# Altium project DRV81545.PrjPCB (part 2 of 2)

## Sheet DRV81545.SchDoc: DRV81545
size 431 x 279 mm; VersionControl_RevNumber: 1; Date: Not shown in title block; ApprovedBy: Not shown in title block; CheckedBy: Not shown in title block; Author: Not shown in title block; CompanyName: Not shown in title block; DrawnBy: Mojtaba Afshar; Engineer: Not shown in title block; Organization: Not shown in title block; Address1: Not shown in title block; Address2: Not shown in title block; Address3: Not shown in title block; Address4: Not shown in title block; DocumentNumber: 1; Revision: 1; SheetNumber: 3; SheetTotal: 5; PageSetup: Record=PageOptions¦CenterHorizontal=True¦CenterVertical=True¦PrintScale=1.00¦XCorrection=1.00¦YCorrection=1.00¦PrintKind=0¦BorderSize=5000000¦LeftOffset=0¦BottomOffset=0¦Orientation=2¦PaperLength=1000¦PaperWidth=1000¦Scale=100¦PaperSource=15¦PrintQuality=600¦MediaType=1¦DitherType=10¦PaperKind=Letter¦PrintScaleMode=1; VersionControl_ProjFolderRevNumber: 1; VersionControl_RevNumberShort: 1; VersionControl_ProjFolderRevNumberShort: 1; Orderable: DRV81545EVM

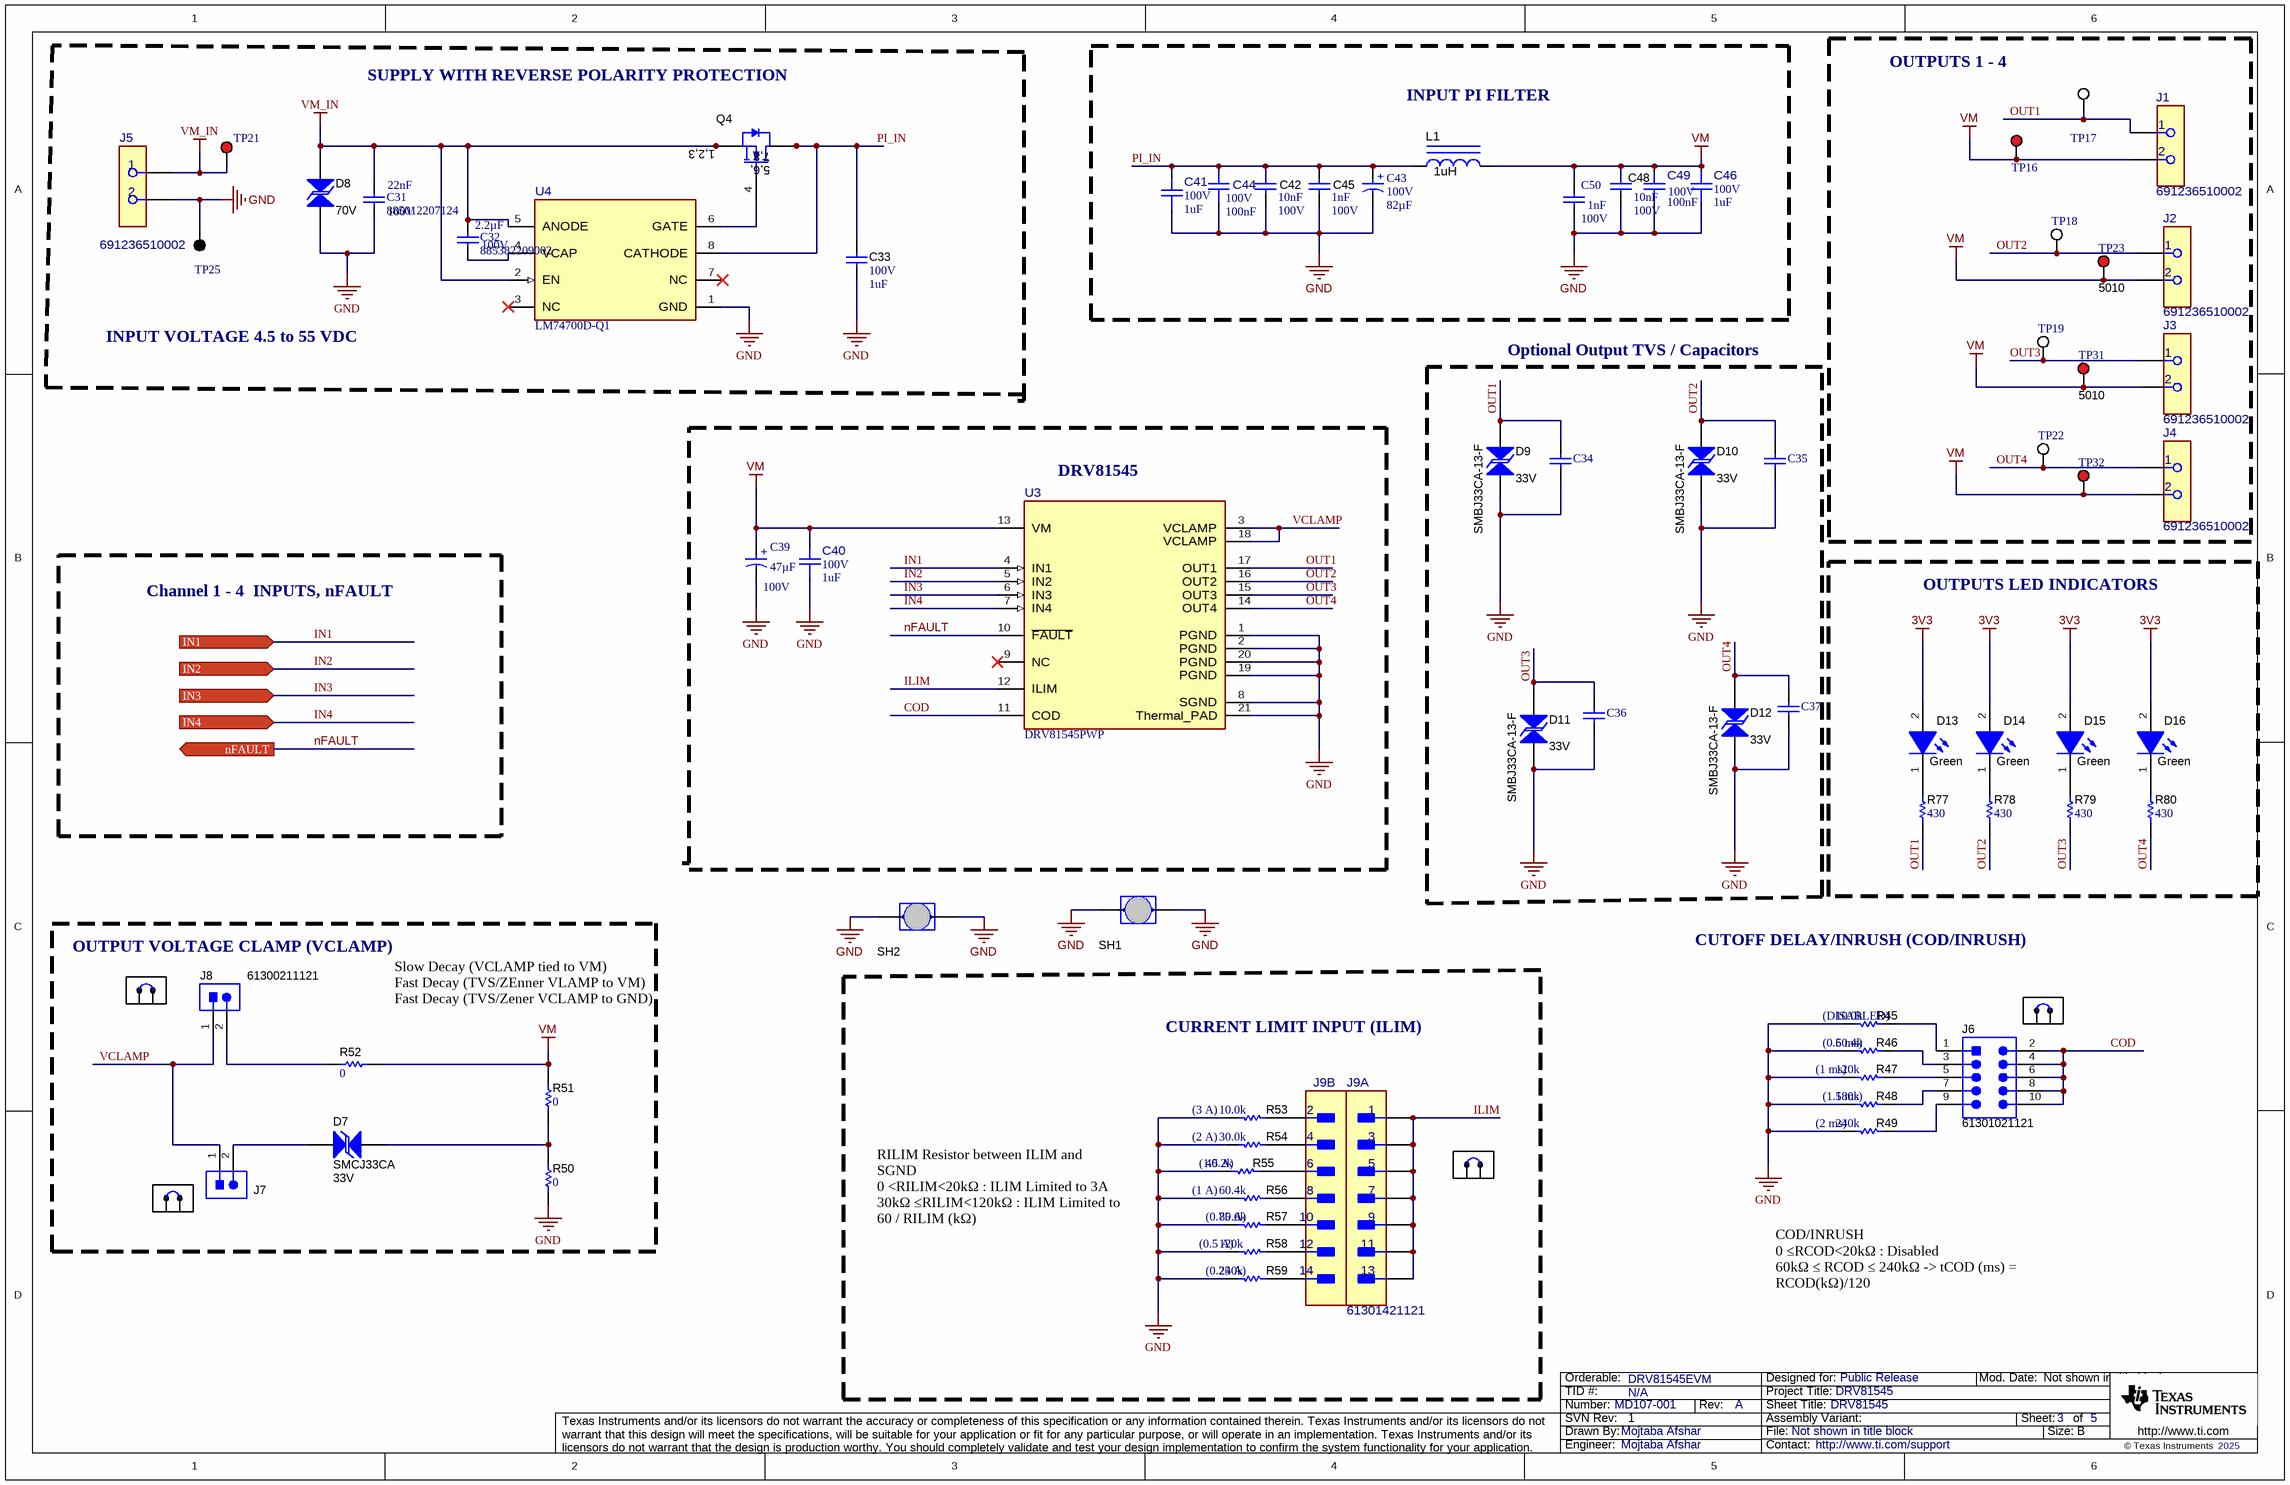
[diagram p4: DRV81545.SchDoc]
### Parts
C31  885012207124  Cap_F: 22nF  Rated Voltage (DC): 100V  [WCAP-CSGP_0805_L2W1.25H0.8_Reflow]
C32  885382209002  Cap_F: 2.2µF  Rated Voltage (DC): 100V  [WCAP-CSST_1210_L3.2W2.5H2.5]
C33  VDC_V: 100V  ValueDisplayed: 1uF  [0805_HV]  (hidden comment: C2012X7S2A105K125AB)
C34  885012207124  [WCAP-CSGP_0805_L2W1.25H0.8_Reflow]  (value not drawn)
C35  885012207124  [WCAP-CSGP_0805_L2W1.25H0.8_Reflow]  (value not drawn)
C36  885012207124  [WCAP-CSGP_0805_L2W1.25H0.8_Reflow]  (value not drawn)
C37  885012207124  [WCAP-CSGP_0805_L2W1.25H0.8_Reflow]  (value not drawn)
C39  Cap_F: 47µF  Rated Voltage (DC): 100V  [WCAP-ATUL_D10H12.5]  (hidden comment: 860040875002)
C40  VDC_V: 100V  ValueDisplayed: 1uF  [FP-885012209069_1210-MFG]  (hidden comment: 885012209069)
C41  VDC_V: 100V  ValueDisplayed: 1uF  [FP-885012209069_1210-MFG]  (hidden comment: 885012209069)
C42  Cap_F: 10nF  VDC_V: 100V  [0603]  (hidden comment: 885012206114)
C43  Cap_F: 82µF  Rated Voltage (DC): 100V  [WCAP-ATUL_D10H20]  (hidden comment: 860040875004)
C44  VDC_V: 100V  Cap_F: 100nF  [FP-885012206120_0603-MFG]  (hidden comment: 885012206120)
C45  Cap_F: 1nF  VDC_V: 100V  [0603]  (hidden comment: 06031C102KAT2A)
C46  VDC_V: 100V  ValueDisplayed: 1uF  [FP-885012209069_1210-MFG]  (hidden comment: 885012209069)
C48  Cap_F: 10nF  VDC_V: 100V  [0603]  (hidden comment: 885012206114)
C49  VDC_V: 100V  Cap_F: 100nF  [FP-885012206120_0603-MFG]  (hidden comment: 885012206120)
C50  value 1nF  Rated Voltage (DC): 100V  [WCAP-CSGP_0603_L1.6W0.8H0.8_Reflow]  (hidden comment: 885012206108)
D7  SMCJ33CA  value 33V  [SMC_Bi]
D8  value 70V  [SMB-Bi]  (hidden comment: SMBJ70CA-13-F)
D9  SMBJ33CA-13-F  value 33V  [SMB-Bi]
D10  SMBJ33CA-13-F  value 33V  [SMB-Bi]
D11  SMBJ33CA-13-F  value 33V  [SMB-Bi]
D12  SMBJ33CA-13-F  value 33V  [SMB-Bi]
D13  value Green  [WL-SMCW_GREEN]  (hidden comment: 150060VS75000)
D14  value Green  [WL-SMCW_GREEN]  (hidden comment: 150060VS75000)
D15  value Green  [WL-SMCW_GREEN]  (hidden comment: 150060VS75000)
D16  value Green  [WL-SMCW_GREEN]  (hidden comment: 150060VS75000)
J1  691236510002  [FP-691236510002_HHR2-MFG]
J2  691236510002  [FP-691236510002_HHR2-MFG]
J3  691236510002  [FP-691236510002_HHR2-MFG]
J4  691236510002  [FP-691236510002_HHR2-MFG]
J5  691236510002  [FP-691236510002_HHR2-MFG]
J6  61301021121  [WURTH_61301021121]
J7  61300211121  [WURTH_61300211121]  (value not drawn)
J8  61300211121  [WURTH_61300211121]
J9  61301421121  [FP-61301421121_HDR14-MFG]  (parts A,B of 2)
L1  ValueDisplayed: 1uH  [WE-HCC_1210]  (hidden comment: 7443320100)
Q4  CSD19502Q5B  [DNK0008A]  (value not drawn)
R45  ValueDisplayed: 10.0k  [0603]  (hidden comment: RC0603FR-0710KL)
R46  ValueDisplayed: 60.4k  [0603]  (hidden comment: RC0603FR-0760K4L)
R47  ValueDisplayed: 120k  [0603]  (hidden comment: RC0603FR-07120KL)
R48  ValueDisplayed: 180k  [0603]  (hidden comment: RC0603FR-07180KL)
R49  ValueDisplayed: 240k  [0603]  (hidden comment: RC0603FR-07240KL)
R50  ValueDisplayed: 0  [1206]  (hidden comment: CRCW12060000Z0EAHP)
R51  ValueDisplayed: 0  [1206]  (hidden comment: CRCW12060000Z0EAHP)
R52  ValueDisplayed: 0  [1206]  (hidden comment: CRCW12060000Z0EAHP)
R53  ValueDisplayed: 10.0k  [0603]  (hidden comment: RC0603FR-0710KL)
R54  ValueDisplayed: 30.0k  [0603]  (hidden comment: RC0603FR-0730KL)
R55  ValueDisplayed: 40.2k  [0603]  (hidden comment: RC0603FR-0740K2L)
R56  ValueDisplayed: 60.4k  [0603]  (hidden comment: RC0603FR-0760K4L)
R57  ValueDisplayed: 80.6k  [0603]  (hidden comment: RC0603FR-0780K6L)
R58  ValueDisplayed: 120k  [0603]  (hidden comment: RC0603FR-07120KL)
R59  ValueDisplayed: 240k  [0603]  (hidden comment: RC0603FR-07240KL)
R77  ValueDisplayed: 430  [0603]  (hidden comment: RC0603JR-07430RL)
R78  ValueDisplayed: 430  [0603]  (hidden comment: RC0603JR-07430RL)
R79  ValueDisplayed: 430  [0603]  (hidden comment: RC0603JR-07430RL)
R80  ValueDisplayed: 430  [0603]  (hidden comment: RC0603JR-07430RL)
SH1  Jumper_2p  [Harwin_D3082-05]  (value not drawn)
SH2  Jumper_2p  [Harwin_D3082-05]  (value not drawn)
SH-J1  60900213421  [Wurth_60900213421]  (value not drawn)
SH-J10  60900213421  [Wurth_60900213421]  (value not drawn)
SH-J11  60900213421  [Wurth_60900213421]  (value not drawn)
SH-J12  60900213421  [Wurth_60900213421]  (value not drawn)
TP16  5010  [Keystone5010]  (value not drawn)
TP17  5012  [Keystone5012]  (value not drawn)
TP18  5012  [Keystone5012]  (value not drawn)
TP19  5012  [Keystone5012]  (value not drawn)
TP21  5010  [Keystone5010]  (value not drawn)
TP22  5012  [Keystone5012]  (value not drawn)
TP23  5010  [Keystone5010]
TP25  5011  [Keystone5011]  (value not drawn)
TP31  5010  [Keystone5010]
TP32  5010  [Keystone5010]  (value not drawn)
U3  DRV81545PWP  [PWP0020AC-MFG]
U4  LM74700D-Q1  [D0008A-MFG]

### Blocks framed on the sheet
INPUT PI FILTER: C41-C46 C48-C50 L1
Optional Output TVS / Capacitors: C34-C37 D9-D12
OUTPUTS LED INDICATORS: D13-D16 R77-R80
CURRENT LIMIT INPUT (ILIM): J9 R53-R59 SH-J11

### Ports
IN1 (in), IN2 (in), IN3 (in), IN4 (in), nFAULT (out)

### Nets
3V3: D13.2(A) D14.2(A) D15.2(A) D16.2(A)
GND: C31.1 C33.2 C34.1 C35.1 C36.1 C37.1 C39.2(N) C40.1 C41.1 C42.1 C43.2(N) C44.1 C45.2 C46.1 C48.1 C49.1 C50.1 D8.1 D9.1 D10.1 D11.1 D12.1 J5.2 R45.1 R46.1 R47.1 R48.1 R49.1 R50.1 R53.1 R54.1 R55.1 R56.1 R57.1 R58.1 R59.1 SH1.1 SH1.2 SH2.1 SH2.2 TP25.1 U3.1(PGND) U3.2(PGND) U3.8(SGND) U3.19(PGND) U3.20(PGND) U3.21(Thermal_PAD) U4.1(GND)
VM: C39.1(P) C40.2 C46.2 C48.2 C49.2 C50.2 J1.2 J2.2 J3.2 J4.2 L1.2 R51.2 R52.2 TP16.1 TP23.1 TP31.1 TP32.1 U3.13(VM)
VM_IN: C31.2 C32.2 D8.2 J5.1 Q4.1(S) Q4.2(S) Q4.3(S) TP21.1 U4.2(EN) U4.5(ANODE)
COD: J6.2 J6.4 J6.6 J6.8 J6.10 U3.11(COD)
ILIM: J9.1 J9.3 J9.5 J9.7 J9.9 J9.11 J9.13 U3.12(ILIM)
IN1: U3.4(IN1) ; port IN1
IN2: U3.5(IN2) ; port IN2
IN3: U3.6(IN3) ; port IN3
IN4: U3.7(IN4) ; port IN4
nFAULT: U3.10(~{FAULT}) ; port nFAULT
OUT1: C34.2 D9.2 J1.1 R77.1 TP17.1 U3.17(OUT1)
OUT2: C35.2 D10.2 J2.1 R78.1 TP18.1 U3.16(OUT2)
OUT3: C36.2 D11.2 J3.1 R79.1 TP19.1 U3.15(OUT3)
OUT4: C37.2 D12.2 J4.1 R80.1 TP22.1 U3.14(OUT4)
PI_IN: C33.1 C41.2 C42.2 C43.1(P) C44.2 C45.1 L1.1 Q4.5(D) Q4.6(D) Q4.7(D) Q4.8(D) Q4.9(D) U4.8(CATHODE)
VCLAMP: J7.1 J8.1 U3.3(VCLAMP) U3.18(VCLAMP)
NetC32_1: C32.1 U4.4(VCAP)
NetD7_1: D7.1 J7.2
NetD7_2: D7.2 R50.2 R51.1
NetD13_1: D13.1(K) R77.2
NetD14_1: D14.1(K) R78.2
NetD15_1: D15.1(K) R79.2
NetD16_1: D16.1(K) R80.2
NetJ6_1: J6.1 R45.2
NetJ6_3: J6.3 R46.2
NetJ6_5: J6.5 R47.2
NetJ6_7: J6.7 R48.2
NetJ6_9: J6.9 R49.2
NetJ8_2: J8.2 R52.1
NetJ9_2: J9.2 R53.2
NetJ9_4: J9.4 R54.2
NetJ9_6: J9.6 R55.2
NetJ9_8: J9.8 R56.2
NetJ9_10: J9.10 R57.2
NetJ9_12: J9.12 R58.2
NetJ9_14: J9.14 R59.2
NetQ4_4: Q4.4(G) U4.6(GATE)

Not connected (* = marked no-connect by the designer): U3 9(NC)*; U4 3(NC)* 7(NC)*

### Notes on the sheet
- SUPPLY WITH REVERSE POLARITY PROTECTION
- OUTPUTS 1 - 4
- INPUT VOLTAGE 4.5 to 55 VDC
- (near U3) DRV81545
- Channel 1 - 4  INPUTS, nFAULT
- OUTPUT VOLTAGE CLAMP (VCLAMP)
- CUTOFF DELAY/INRUSH (COD/INRUSH)
- Slow Decay (VCLAMP tied to VM)
  Fast Decay (TVS/ZEnner VLAMP to VM)
  Fast Decay (TVS/Zener VCLAMP to GND)
- (DISABLED)
- (1 ms)
- (0.5 ms)
- (1.5 ms)
- (2 A)
- (3 A)
- (1.5 A)
- (2 ms)
- RILIM Resistor between ILIM and SGND
  0 <RILIM<20kΩ : ILIM Limited to 3A
  30kΩ ≤RILIM<120kΩ : ILIM Limited to 60 / RILIM (kΩ)
  120kΩ ≤RILIM : ILIM Limited to 60 / RILIM (kΩ), Linearity is not guaranteed.
- (1 A)
- (0.75 A)
- (0.5 A)
- (0.25 A)
- COD/INRUSH
  0 ≤RCOD<20kΩ : Disabled
  60kΩ ≤ RCOD ≤ 240kΩ -> tCOD (ms) = RCOD(kΩ)/120

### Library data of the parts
C31 = CMP-0119538-1: WCAP-CSGP Multilayer Ceramic Chip Capacitor, General Purpose, size 0805, X7R, 22nF, 100VDC; Manufacturer: Wurth Elektronik; Capacitance Tolerance: +/-10%; Case/Size Code: 0805; Dissipation Factor: 2.5%; Insulation Resistance: 4.5GOhm; Technical Reference: X7R0805223K100DFCT10000
C32 = CMP-0119921-1: WCAP-CSST Multilayer Ceramic Chip Capacitor, Soft Termination, size 1210, X7R Class II, 2.2µF, 100VDC; Manufacturer: Wurth Elektronik; Capacitance Tolerance: +/-10%; Case/Size Code: 1210; Dissipation Factor: 5%; Insulation Resistance: 0.05GOhm; Technical Reference: X7R1210225K100DFCT1S000
C33 = CMP-0007891-2: CAP, CERM, 1 uF, 100 V, +/- 10%, X7S, 0805; Manufacturer: TDK; TaMin_C: -55°C; ESR_ohm: 8.255m; Polarized: N; SizeAreaWB_mm2: 6.75; Value1: 0.008255 ohm; U/M: EA; Value: 1uF; TaMax_C: 125°C; SizeZ_mm: 1.45; SizeX_mm: 2; SizeY_mm: 1.25; Cap_Case: 0805; SizeArea_mm2: 2.5; Cap_F: 1µF; IRMS_A: 2.27442A; AEC Category: Q200
C34-C37 = CMP-0119538-1: WCAP-CSGP Multilayer Ceramic Chip Capacitor, General Purpose, size 0805, X7R, 22nF, 100VDC; Manufacturer: Wurth Elektronik; Capacitance Tolerance: +/-10%; Case/Size Code: 0805; Dissipation Factor: 2.5%; Insulation Resistance: 4.5GOhm; Rated Voltage (DC): 100V; Technical Reference: X7R0805223K100DFCT10000
C39 = CMP-0102580-1: WCAP-ATUL Aluminum Electrolytic Capacitor, Radial, THT, D10 x H12.5mm, 47µF, 100V; Manufacturer: Wurth Elektronik; Capacitance Tolerance: 20%; Dissipation Factor: 9%; Endurance: 7000h; Leakage Current: 47uA; Ripple Current: 400mA; Technical Reference: ATDF125470M100DSPA9G000; Value: 47uF
C40 C41 C46 = CMP-0097312-1: 1 µF ±10% 100V Ceramic Capacitor X7R 1210 (3225 Metric); Manufacturer: Wurth Electronics; AEC Qualified: No; SizeZ_mm: 2.2mm; Cap_F: 1µF; Value: 1µF; TempCo: 15%
C42 C48 = CMP-0079993-1: CAP, CERM, 0.01 µF, 100 V,+/- 10%, X7R, 0603; Manufacturer: Wurth Elektronik; TaMin_C: -55°C; Polarized: N; SizeAreaWB_mm2: 4.68; U/M: EA; Value: 0.01uF; TaMax_C: 105°C; SizeZ_mm: 1; SizeX_mm: 1.6; SizeY_mm: 0.8; SizeArea_mm2: 1.28; AEC Category: Q200; ValueDisplayed: 0.01µF
C43 = CMP-0102582-1: WCAP-ATUL Aluminum Electrolytic Capacitor, Radial, THT, D10 x H20mm, 82µF, 100V; Manufacturer: Wurth Elektronik; Capacitance Tolerance: 20%; Dissipation Factor: 9%; Endurance: 7000h; Leakage Current: 82uA; Ripple Current: 600mA; Technical Reference: ATDF200820M100DSPAAG000
C44 C49 = CMP-0097294-1: 0.1 µF ±10% 100V Ceramic Capacitor X7R 0603 (1608 Metric); Manufacturer: Wurth Electronics; TempCo: 15%; SizeZ_mm: 0.87mm; Value: 100nF; AEC Qualified: No
C45 = CMP-0006724-5: CAP, CERM, 1000 pF, 100 V, +/- 10%, X7R, 0603; Manufacturer: AVX; TaMin_C: -55°C; ESR_ohm: 2.76d; Polarized: N; SizeAreaWB_mm2: 4.68; Value1: 0.276 ohm; U/M: EA; Value: 1000pF; TaMax_C: 125°C; SizeZ_mm: 1; SizeX_mm: 1.6; SizeY_mm: 0.8; SizeArea_mm2: 1.28; AEC Category: Q200
C50 = CMP-0119409-1: WCAP-CSGP Multilayer Ceramic Chip Capacitor, General Purpose, size 0603, X7R, 1nF, 100VDC; Manufacturer: Wurth Elektronik; Capacitance Tolerance: +/-10%; Dissipation Factor: 2.5%; Insulation Resistance: 10GOhm; Technical Reference: X7R0603102K100DFCT10000
D7 = CMP-0005695-3: Diode, TVS, Bi, 33 V, SMC; Manufacturer: Bourns; SizeZ_mm: 2.6; Ppk: 1.5kW; Value1: 1500W; AEC Category: Q101; SizeArea_mm2: 50.5686; SizeX_mm: 8.13; SizeAreaWB_mm2: 83.2686; SizeY_mm: 6.22
D8 = CMP-0005587-3: Diode, TVS, Bi, 70 V, SMB; Manufacturer: Diodes Inc.; AEC Category: Q101; SizeX_mm: 5.6; SizeY_mm: 3.81; Ppk: 600W; SizeZ_mm: 2.6; SizeArea_mm2: 21.336; SizeAreaWB_mm2: 44.156
D9-D12 = CMP-0005564-3: Diode, TVS, Bi, 33 V, SMB; Manufacturer: Diodes Inc.; SizeX_mm: 5.6; Ppk: 600W; SizeAreaWB_mm2: 44.156; SizeZ_mm: 2.6; SizeArea_mm2: 21.336; SizeY_mm: 3.81; AEC Category: Q101
D13-D16 = CMP-0002894-2: LED, Green, SMD; Manufacturer: Wurth Elektronik; Type: AlInGaP; Value2: 2V; Io_A: 20mA; Value1: W
J1-J5 = CMP-0121282-1: 2 Position Wire to Board Terminal Block Horizontal with Board 0.200" (5.08mm) Through Hole; Manufacturer: Wurth Electronics; Current_A: 20A; Row_Count: 1; Voltage_V: 300V; AEC Qualified: No; Conn Gender: Female; Is Female: yes; Max Wire Gauge: 12; Min Wire Gauge: 30; SizeZ_mm: 18.1mm
J6 = CMP-0054806-3: Header, 2.54 mm, 5x2, Gold, TH; Manufacturer: Wurth Elektronik; Green_Lifecycle: Active; Green_REACh: Passed; Cert_UL: Y; Current_A: 3A; Gender: Male; Pitch_mm: 2.54; Row_Count: 2; Shrouded: N; Voltage_V: 250V
J7 J8 = CMP-0054794-2: Header, 2.54 mm, 2x1, Gold, TH; Manufacturer: Wurth Elektronik; Shrouded: N; Gender: Male; Green_REACh: Passed; Pitch_mm: 2.54; Green_Lifecycle: Active; Row_Count: 1; Cert_UL: Y
J9 = CMP-0097334-1: Connector Header Through Hole 14 position 0.100" (2.54mm); Manufacturer: Wurth Electronics; AEC Qualified: No; Conn Gender: Male; Current_A: 3A; Voltage_V: 250V; ContactFinish: Gold; Row_Count: 2; SizeZ_mm: 8.89mm; Conn Orientation: Straight
L1 = CMP-0063986-1: Inductor, Shielded Drum Core, Ferrite, 1 uH, 24 A, 0.0012 ohm, SMD; Manufacturer: Wurth Elektronik; Isat: 32A @ 30% inductance drop; Irms: 24A @ 50C rise; Green_Lifecycle: Active; SizeAreaWB_mm2: 188.94; DCR_ohm: 1.2m; Green_REACh: Passed; Value: 1uH; Imax_A: 24A; SizeZ_mm: 10; SizeX_mm: 12.1; SizeY_mm: 11.4; SizeArea_mm2: 137.94; Ind_H: 1µH; AEC Category: Q200
Q4 = CMP-0000915-2: MOSFET, N-CH, 80 V, 100 A, DNK0008A (VSON-CLIP-8); Alternate Manufacturer: None; Manufacturer: Texas Instruments; SizeZ_mm: 1; ChType: N; Value2: 48 nC; VdsMax_V: 80V; SizeX_mm: 6; SizeY_mm: 5; Vgs_V: 20V; Value: 80V; SizeArea_mm2: 30; AEC Category: Q101; IdsMax_A: 100A; SizeAreaWB_mm2: 56; U/M: EA; QgTyp_nC: 48
R45 R53 = CMP-0022746-5: RES, 10.0 k, 1%, 0.1 W, 0603; Manufacturer: Yageo; Power_W: 100mW; TempCo: 100 ppm/C; Value_Code: 10k0; Value: 10.0k; EIA_Code: E96; Res_ohm: 10k; SizeX_mm: 1.6; SizeY_mm: 0.8; SizeZ_mm: 1; Value2: 0.1W; SizeArea_mm2: 1.28; AEC Qualified: N; VDC_V: 75V; AEC Category: Q200; SizeAreaWB_mm2: 4.68
R46 R56 = CMP-0023212-5: RES, 60.4 k, 1%, 0.1 W, 0603; Manufacturer: Yageo; Power_W: 100mW; TempCo: 100 ppm/C; Value_Code: 60k4; Value: 60.4k; EIA_Code: E96; SizeX_mm: 1.6; SizeY_mm: 0.8; SizeZ_mm: 1; Value2: 0.1W; SizeArea_mm2: 1.28; AEC Qualified: N; VDC_V: 75V; AEC Category: Q200; SizeAreaWB_mm2: 4.68
R47 R58 = CMP-0022768-4: RES, 120 k, 1%, 0.1 W, 0603; Manufacturer: Yageo; Power_W: 100mW; TempCo: 100 ppm/C; Value: 120k; SizeX_mm: 1.6; SizeY_mm: 0.8; SizeZ_mm: 1; Value2: 0.1W; SizeArea_mm2: 1.28; AEC Qualified: N; VDC_V: 75V; AEC Category: Q200; SizeAreaWB_mm2: 4.68
R48 = CMP-0022844-4: RES, 180 k, 1%, 0.1 W, 0603; Manufacturer: Yageo; Power_W: 100mW; TempCo: 100 ppm/C; Value: 180k; SizeX_mm: 1.6; SizeY_mm: 0.8; SizeZ_mm: 1; Value2: 0.1W; SizeArea_mm2: 1.28; AEC Qualified: N; VDC_V: 75V; AEC Category: Q200; SizeAreaWB_mm2: 4.68
R49 R59 = CMP-0022937-4: RES, 240 k, 1%, 0.1 W, 0603; Manufacturer: Yageo; Power_W: 100mW; TempCo: 100 ppm/C; Value: 240k; SizeX_mm: 1.6; SizeY_mm: 0.8; SizeZ_mm: 1; Value2: 0.1W; SizeArea_mm2: 1.28; AEC Qualified: N; VDC_V: 75V; AEC Category: Q200; SizeAreaWB_mm2: 4.68
R50-R52 = CMP-0086176-1: RES, 0, 0.75 W, AEC-Q200 Grade 0, 1206; Manufacturer: Vishay-Dale; Value: 0; SizeY_mm: 1.6; SizeX_mm: 3.2; Tolerance_%: 0%; SizeArea_mm2: 5.12; EIA_Code: E96; SizeAreaWB_mm2: 10.92; Power_W: 750mW; AEC Qualified: Y; SizeZ_mm: 1.35; Value2: 0.75W; AEC Category: Q200; VDC_V: 200V
R54 = CMP-0023020-5: RES, 30.0 k, 1%, 0.1 W, 0603; Manufacturer: Yageo; Power_W: 100mW; TempCo: 100 ppm/C; Value_Code: 30k0; Value: 30.0k; Res_ohm: 30k; SizeX_mm: 1.6; SizeY_mm: 0.8; SizeZ_mm: 1; Value2: 0.1W; SizeArea_mm2: 1.28; AEC Qualified: N; VDC_V: 75V; AEC Category: Q200; SizeAreaWB_mm2: 4.68
R55 = CMP-0023098-5: RES, 40.2 k, 1%, 0.1 W, 0603; Manufacturer: Yageo; Power_W: 100mW; TempCo: 100 ppm/C; Value_Code: 40k2; Value: 40.2k; EIA_Code: E96; SizeX_mm: 1.6; SizeY_mm: 0.8; SizeZ_mm: 1; Value2: 0.1W; SizeArea_mm2: 1.28; AEC Qualified: N; VDC_V: 75V; AEC Category: Q200; SizeAreaWB_mm2: 4.68
R57 = CMP-0023285-5: RES, 80.6 k, 1%, 0.1 W, 0603; Manufacturer: Yageo; Power_W: 100mW; TempCo: 100 ppm/C; Value_Code: 80k6; EIA_Code: E96; SizeX_mm: 1.6; SizeY_mm: 0.8; SizeZ_mm: 1; Value2: 0.1W; Value: 80.6k; SizeArea_mm2: 1.28; AEC Qualified: N; VDC_V: 75V; AEC Category: Q200; SizeAreaWB_mm2: 4.68
R77-R80 = CMP-0025922-5: RES, 430, 5%, 0.1 W, 0603; Manufacturer: Yageo; Power_W: 100mW; TempCo: 100 ppm/C; Value_Code: 430R; Value: 430; EIA_Code: E24; SizeX_mm: 1.6; SizeY_mm: 0.8; SizeZ_mm: 1; Value2: 0.1W; SizeArea_mm2: 1.28; AEC Qualified: N; VDC_V: 75V; AEC Category: Q200; SizeAreaWB_mm2: 4.68
SH1 SH2 = CMP-0075110-1: 1mm Uninsulated Shorting Plug, 10.16mm spacing, TH; PartNumber: D3082-05; Manufacturer: Harwin; CNHeader: False; CompType: Jumper Wire; Green_Lifecycle: Active; Green_REACh: Passed
SH-J1 SH-J10-SH-J12 = CMP-0003761-2: Shunt, 2.54mm, Gold, Black; Manufacturer: Wurth Elektronik
TP16 TP23 TP31 TP32 = CMP-0055147-2: Test Point, Multipurpose, Red, TH; Manufacturer: Keystone Electronics; CT: TRUE; ContactFinish: Silver; Green_Lifecycle: Active; CNHeader: FALSE; Green_REACh: Passed
TP17-TP19 TP22 = CMP-0055149-2: Test Point, Multipurpose, White, TH; Manufacturer: Keystone Electronics; ContactFinish: Silver; CT: TRUE; CNHeader: FALSE; Green_Lifecycle: Active; Green_REACh: Passed
TP21 = CMP-0055147-2: Test Point, Multipurpose, Red, TH; Manufacturer: Keystone Electronics; CNHeader: FALSE; Green_Lifecycle: Active; Green_REACh: Passed; ContactFinish: Silver; CT: TRUE
TP25 = CMP-0055148-2: Test Point, Multipurpose, Black, TH; Manufacturer: Keystone Electronics; CNHeader: FALSE; Green_Lifecycle: Active; Green_REACh: Passed; ContactFinish: Silver; CT: TRUE
U3 = CMP-0125514-1: Manufacturer: Texas Instruments; SizeZ_mm: 1.2mm; AEC Qualified: Unknown; AEC Grade: NA; Standoff Height: 0.05mm
U4 = CMP-0125797-1: Manufacturer: Texas Instruments; SizeZ_mm: 1.75mm; Standoff Height: 0.11mm

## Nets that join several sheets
3V3: DRV81545_M0 (9 pins), DRV81545 (D13.2 D14.2 D15.2 D16.2)
3V3_MCU: DRV81545_XDS110 (J11.4), DRV81545_M0 (12 pins)
GND: DRV81545_XDS110 (55 pins), DRV81545_M0 (32 pins), DRV81545 (48 pins)
VM: DRV81545_M0 (D18.2 R4.2 R81.2), DRV81545 (18 pins)
BSL_INVOKE: DRV81545_XDS110 (XDS1.42), DRV81545_M0 (R32.2 TP8.1 U1.11)
IN1: DRV81545_M0 (J10.6 TP13.1), DRV81545 (U3.4)
IN2: DRV81545_M0 (J10.8 TP15.1), DRV81545 (U3.5)
IN3: DRV81545_M0 (J10.10 TP12.1), DRV81545 (U3.6)
IN4: DRV81545_M0 (J10.12 TP14.1), DRV81545 (U3.7)
nFAULT: DRV81545_M0 (J10.4 R33.1 R34.1 TP11.1), DRV81545 (U3.10)
RST: DRV81545_XDS110 (J11.10), DRV81545_M0 (5 pins)
SWCLK: DRV81545_XDS110 (J11.14), DRV81545_M0 (U1.13)
SWDIO: DRV81545_XDS110 (J11.12), DRV81545_M0 (U1.12)
UART1_RX: DRV81545_XDS110 (J11.6), DRV81545_M0 (U1.53)
UART1_TX: DRV81545_XDS110 (J11.8), DRV81545_M0 (U1.52)

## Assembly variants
DRV81545PWP: not fitted C? C? C? C? D8 D9 D10 D11 D12 J12 J13 R36 R37 R39 R42 R43 R50 R51 Y1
